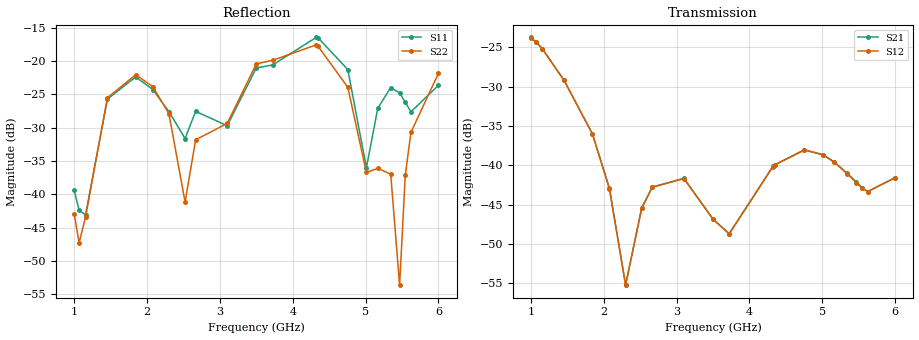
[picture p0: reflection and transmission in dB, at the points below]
!Agilent Technologies,E8364B,MY43040528,A.07.50.67
!Agilent E8364B: A.07.50.67
!Date: Sunday, March 01, 2026 20:51:58
!Correction: S11(Full 2 Port(1,2))
!S21(Full 2 Port(1,2))
!S12(Full 2 Port(1,2))
!S22(Full 2 Port(1,2))
!S2P File: Measurements: S11, S21, S12, S22:
# Hz S  dB  R 50
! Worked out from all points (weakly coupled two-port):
!   451 points, 1 GHz to 6 GHz, reference 50 ohm
!   highest |S21| = -23.72 dB at 1 GHz (marker M1); lowest = -55.2 dB at 2.3 GHz (marker M2)
!   lowest |S11| = -43.1 dB at 1.156 GHz (marker M3), VSWR 1.01, Z = 49.5 + j0.528 ohm
!   |S11| at or under -10 dB: start of sweep to end of sweep
!   |S22| runs from -53.6 to -17.1 dB; largest |S21 - S12| = 0.00019
!   S11 on the Smith chart (normalised r, x): 1 GHz: 1.01, +0.02; 4.322 GHz: 1.24, -0.24; 6 GHz: 0.99, -0.13
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1e9  -39.40 64.4  -23.72 148.9  -23.75 148.9  -42.90 4.8
1.066667e9  -42.36 93.7  -24.28 110.3  -24.31 110.4  -47.29 46.2
1.155556e9  -43.09 130.5  -25.14 59.1  -25.16 59.1  -43.43 87.6
1.455556e9  -25.70 164.2  -29.18 -110.7  -29.19 -110.8  -25.51 95.5
1.844444e9  -22.36 93.8  -35.98 38.7  -36.00 38.8  -22.04 3.0
2.077778e9  -24.26 66.9  -42.89 -84.2  -42.96 -84.2  -23.82 -40.8
2.3e9  -27.57 48.7  -55.20 -131.2  -55.22 -131.3  -27.88 -81.9
2.522222e9  -31.62 76.8  -45.38 172.5  -45.43 172.5  -41.17 -58.2
2.666667e9  -27.54 83.0  -42.75 97.1  -42.78 97.0  -31.81 -26.4
3.1e9  -29.69 67.6  -41.64 -137.5  -41.68 -137.6  -29.36 -44.3
3.5e9  -21.01 50.5  -46.82 24.0  -46.84 24.1  -20.41 -106.9
3.722222e9  -20.58 31.4  -48.69 -51.5  -48.71 -51.7  -19.88 -139.9
4.322222e9  -16.43 -38.7  -40.13 26.5  -40.16 26.5  -17.55 109.0
4.344444e9  -16.46 -42.2  -39.93 14.3  -39.96 14.3  -17.72 103.8
4.755556e9  -21.26 -110.1  -38.02 140.7  -38.05 140.7  -23.92 -2.6
5.011111e9  -36.02 -91.7  -38.63 -10.9  -38.66 -10.9  -36.72 -119.6
5.166667e9  -27.09 -49.6  -39.58 -105.1  -39.62 -105.1  -36.10 107.3
5.344444e9  -23.97 -77.4  -41.02 143.3  -41.06 143.3  -36.97 35.3
5.466667e9  -24.78 -94.9  -42.14 62.2  -42.18 62.2  -53.64 94.7
5.544444e9  -26.16 -99.7  -42.82 8.2  -42.85 8.0  -37.16 121.8
5.622222e9  -27.62 -97.6  -43.32 -47.6  -43.35 -47.5  -30.70 104.4
6e9  -23.62 -90.6  -41.54 43.8  -41.57 43.8  -21.83 -2.2
